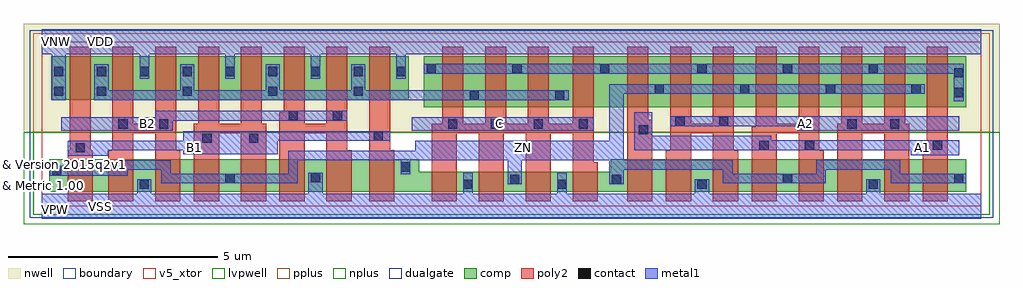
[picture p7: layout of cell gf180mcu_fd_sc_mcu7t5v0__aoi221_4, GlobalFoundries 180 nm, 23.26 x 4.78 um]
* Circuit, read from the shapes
.subckt gf180mcu_fd_sc_mcu7t5v0__aoi221_4 A1 A2 B1 B2 C VDD VNW VSS ZN
XM1 n1 B1 ZN VSUBS nfet_05v0 w=0.77u l=0.6u
XM2 VSS B2 n1 VSUBS nfet_05v0 w=0.77u l=0.6u
XM3 n2 B2 VSS VSUBS nfet_05v0 w=0.77u l=0.6u
XM4 ZN B1 n2 VSUBS nfet_05v0 w=0.77u l=0.6u
XM5 n3 B1 ZN VSUBS nfet_05v0 w=0.77u l=0.6u
XM6 VSS B2 n3 VSUBS nfet_05v0 w=0.77u l=0.6u
XM7 n4 B2 VSS VSUBS nfet_05v0 w=0.77u l=0.6u
XM8 ZN B1 n4 VSUBS nfet_05v0 w=0.77u l=0.6u
XM9 VSS C ZN VSUBS nfet_05v0 w=0.48u l=0.6u m=4
XM10 n5 A1 ZN VSUBS nfet_05v0 w=0.77u l=0.6u
XM11 VSS A2 n5 VSUBS nfet_05v0 w=0.77u l=0.6u
XM12 n6 A2 VSS VSUBS nfet_05v0 w=0.77u l=0.6u
XM13 ZN A1 n6 VSUBS nfet_05v0 w=0.77u l=0.6u
XM14 n7 A1 ZN VSUBS nfet_05v0 w=0.77u l=0.6u
XM15 VSS A2 n7 VSUBS nfet_05v0 w=0.77u l=0.6u
XM16 n8 A2 VSS VSUBS nfet_05v0 w=0.77u l=0.6u
XM17 ZN A1 n8 VSUBS nfet_05v0 w=0.77u l=0.6u
XM18 n9 B1 VDD VNW pfet_05v0 w=1.035u l=0.5u m=4
XM19 VDD B2 n9 VNW pfet_05v0 w=1.035u l=0.5u m=4
XM20 n9 C n10 VNW pfet_05v0 w=1.215u l=0.5u m=4
XM21 ZN A1 n10 VNW pfet_05v0 w=1.215u l=0.5u m=4
XM22 n10 A2 ZN VNW pfet_05v0 w=1.215u l=0.5u m=4
.ends

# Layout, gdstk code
import gdstk
lib = gdstk.Library(unit=1e-6, precision=1e-09)
def R(c, l, rs):  # rectangles x0, y0, x1, y1
    for r in rs: c.add(gdstk.rectangle(r[:2], r[2:], *l))
def A(c, l, x, y, w, h, nx, ny, dx, dy):  # array of equal rectangles
    R(c, l, [(x+i*dx, y+j*dy, x+i*dx+w, y+j*dy+h) for i in range(nx) for j in range(ny)])
def P(c, l, *ps):  # polygons
    for p in ps: c.add(gdstk.Polygon(p, *l))
boundary = (0, 0)
nwell = (21, 0)
comp = (22, 0)
poly2 = (30, 0)
pplus = (31, 0)
nplus = (32, 0)
contact = (33, 0)
metal1 = (34, 0)
dualgate = (55, 0)
v5_xtor = (112, 1)
lvpwell = (204, 0)

gf180mcu_fd_sc_mcu7t5v0_ = lib.new_cell('gf180mcu_fd_sc_mcu7t5v0__aoi221_4')
R(gf180mcu_fd_sc_mcu7t5v0_, boundary, [(0,0,22.4,3.92)])
R(gf180mcu_fd_sc_mcu7t5v0_, nwell, [(-0.43,1.76,22.83,4.35)])
R(gf180mcu_fd_sc_mcu7t5v0_, comp, [(9.11,2.36,22.04,3.575), (0.23,2.54,8.75,3.575)])
P(gf180mcu_fd_sc_mcu7t5v0_, comp, [(0.18,0.345),(0.18,1.115),(9,1.115),(9,0.825),(13.56,0.825),(13.56,1.115),(22.04,1.115),(22.04,0.345)])
P(gf180mcu_fd_sc_mcu7t5v0_, poly2, [(0.62,0.12),(0.62,1.335),(0.67,1.335),(0.67,3.8),(1.17,3.8),(1.17,1.335),(1.22,1.335),(1.22,0.12)],
  [(1.59,0.12),(1.59,1.335),(1.69,1.335),(1.69,3.8),(2.19,3.8),(2.19,1.97),(2.71,1.97),(2.71,3.8),(3.21,3.8),(3.21,1.335),(3.31,1.335),(3.31,0.12),(2.71,0.12),(2.71,1.74),(2.19,1.74),(2.19,0.12)],
  [(3.63,0.12),(3.63,1.97),(3.73,1.97),(3.73,3.8),(4.23,3.8),(4.23,1.97),(4.75,1.97),(4.75,3.8),(5.25,3.8),(5.25,1.97),(5.35,1.97),(5.35,0.12),(4.75,0.12),(4.75,1.74),(4.23,1.74),(4.23,0.12)],
  [(5.67,0.12),(5.67,2.24),(5.77,2.24),(5.77,3.8),(6.27,3.8),(6.27,1.97),(6.79,1.97),(6.79,3.8),(7.29,3.8),(7.29,1.335),(7.39,1.335),(7.39,0.12),(6.79,0.12),(6.79,1.74),(6.27,1.74),(6.27,0.12)],
  [(7.81,0.12),(7.81,3.8),(8.31,3.8),(8.31,1.335),(8.41,1.335),(8.41,0.12)],
  [(9.3,0.12),(9.3,1.97),(9.55,1.97),(9.55,3.8),(10.05,3.8),(10.05,1.97),(10.57,1.97),(10.57,3.8),(11.07,3.8),(11.07,1.97),(11.59,1.97),(11.59,3.8),(12.09,3.8),(12.09,1.97),(12.66,1.97),(12.66,3.8),(13.16,3.8),(13.16,1.045),(13.26,1.045),(13.26,0.12),(12.66,0.12),(12.66,1.74),(12.14,1.74),(12.14,0.12),(11.54,0.12),(11.54,1.74),(11.02,1.74),(11.02,0.12),(10.42,0.12),(10.42,1.74),(9.9,1.74),(9.9,0.12)],
  [(13.96,0.12),(13.96,3.8),(14.46,3.8),(14.46,2.06),(14.56,2.06),(14.56,0.12)],
  [(14.88,0.12),(14.88,1.335),(14.98,1.335),(14.98,3.8),(15.48,3.8),(15.48,1.97),(16,1.97),(16,3.8),(16.5,3.8),(16.5,1.335),(16.6,1.335),(16.6,0.12),(16,0.12),(16,1.74),(15.48,1.74),(15.48,0.12)],
  [(16.92,0.12),(16.92,1.89),(17.02,1.89),(17.02,3.8),(17.52,3.8),(17.52,1.97),(18.04,1.97),(18.04,3.8),(18.54,3.8),(18.54,1.335),(18.64,1.335),(18.64,0.12),(18.04,0.12),(18.04,1.74),(17.52,1.74),(17.52,0.12)],
  [(18.96,0.12),(18.96,1.97),(19.06,1.97),(19.06,3.8),(19.56,3.8),(19.56,1.97),(20.08,1.97),(20.08,3.8),(20.58,3.8),(20.58,1.97),(20.68,1.97),(20.68,0.12),(20.08,0.12),(20.08,1.74),(19.56,1.74),(19.56,0.12)],
  [(21,0.12),(21,1.335),(21.1,1.335),(21.1,3.8),(21.6,3.8),(21.6,0.12)])
R(gf180mcu_fd_sc_mcu7t5v0_, pplus, [(-0.2,1.76,22.6,4.12)])
R(gf180mcu_fd_sc_mcu7t5v0_, nplus, [(-0.2,-0.2,22.6,1.76)])
A(gf180mcu_fd_sc_mcu7t5v0_, contact, 9.69, 1.85, 0.22, 0.22, 3, 1, 1.02, 0)
A(gf180mcu_fd_sc_mcu7t5v0_, contact, 1.32, 2.63, 0.22, 0.22, 4, 1, 2.04, 0)
A(gf180mcu_fd_sc_mcu7t5v0_, contact, 14.61, 2.685, 0.22, 0.22, 4, 1, 2.04, 0)
A(gf180mcu_fd_sc_mcu7t5v0_, contact, 0.3, 3.1, 0.22, 0.22, 9, 1, 1.02, 0)
A(gf180mcu_fd_sc_mcu7t5v0_, contact, 15.63, 3.165, 0.22, 0.22, 3, 1, 2.04, 0)
R(gf180mcu_fd_sc_mcu7t5v0_, contact, [(2.34,0.415,2.56,0.635), (10.05,0.415,10.27,0.635), (12.29,0.415,12.51,0.635), (15.63,0.415,15.85,0.635), (19.71,0.415,19.93,0.635), (11.17,0.535,11.39,0.755), (13.59,0.535,13.81,0.755), (4.38,0.55,4.6,0.77), (17.67,0.55,17.89,0.77), (21.75,0.55,21.97,0.77), (6.42,0.57,6.64,0.79), (0.25,0.735,0.47,0.955), (8.56,0.825,8.78,1.045), (0.81,1.285,1.03,1.505), (17.11,1.345,17.33,1.565), (18.19,1.345,18.41,1.565), (21.245,1.345,21.465,1.565), (3.835,1.51,4.055,1.73), (4.945,1.51,5.165,1.73), (7.915,1.565,8.135,1.785), (14.235,1.715,14.455,1.935), (1.83,1.85,2.05,2.07), (2.805,1.85,3.025,2.07), (12.8,1.85,13.02,2.07), (19.205,1.85,19.425,2.07), (20.225,1.85,20.445,2.07), (15.105,1.915,15.325,2.135), (16.15,1.915,16.37,2.135), (5.89,2.045,6.11,2.265), (6.945,2.045,7.165,2.265), (10.2,2.535,10.42,2.755), (12.24,2.535,12.46,2.755), (21.75,2.6,21.97,2.82), (0.3,2.63,0.52,2.85), (21.75,3.07,21.97,3.29), (9.18,3.165,9.4,3.385), (11.22,3.165,11.44,3.385), (13.31,3.165,13.53,3.385)])
R(gf180mcu_fd_sc_mcu7t5v0_, metal1, [(8.82,1.8,13.16,2.12)])
P(gf180mcu_fd_sc_mcu7t5v0_, metal1, [(0.465,1.8),(0.465,2.12),(2.71,2.12),(2.71,2.27),(7.29,2.27),(7.29,2.04),(3.125,2.04),(3.125,1.8)],
  [(0.62,1.2),(0.62,1.56),(3.38,1.56),(3.38,1.79),(8.31,1.79),(8.31,1.555),(5.63,1.555),(5.63,1.24),(3.38,1.24),(3.38,1.33),(1.59,1.33),(1.59,1.2)],
  [(1.26,2.53),(1.26,3.38),(1.6,3.38),(1.6,2.76),(3.3,2.76),(3.3,3.38),(3.64,3.38),(3.64,2.76),(5.34,2.76),(5.34,3.38),(5.68,3.38),(5.68,2.76),(7.38,2.76),(7.38,3.38),(7.72,3.38),(7.72,2.76),(12.56,2.76),(12.56,2.53)],
  [(20.72,1.22),(20.72,1.335),(14.12,1.335),(14.12,2.245),(14.55,2.245),(14.55,1.675),(17.39,1.675),(17.39,1.57),(21.865,1.57),(21.865,1.22)],
  [(18.01,1.8),(18.01,1.91),(14.98,1.91),(14.98,2.14),(21.865,2.14),(21.865,1.8)],
  [(21.745,2.5),(21.745,3.16),(9.11,3.16),(9.11,3.39),(21.975,3.39),(21.975,2.5)],
  [(11.11,0.53),(11.11,1.095),(8.785,1.095),(8.785,0.765),(8.555,0.765),(8.555,1.095),(6.11,1.095),(6.11,0.545),(2.85,0.545),(2.85,0.87),(2.05,0.87),(2.05,0.73),(0.19,0.73),(0.19,0.96),(1.82,0.96),(1.82,1.1),(3.08,1.1),(3.08,0.78),(5.88,0.78),(5.88,1.325),(8.905,1.325),(8.905,1.56),(13.53,1.56),(13.53,2.91),(21.05,2.91),(21.05,2.68),(13.88,2.68),(13.88,1.105),(16.47,1.105),(16.47,0.78),(18.46,0.78),(18.46,1.105),(20.47,1.105),(20.47,0.775),(22.04,0.775),(22.04,0.545),(20.24,0.545),(20.24,0.87),(18.69,0.87),(18.69,0.545),(16.24,0.545),(16.24,0.875),(13.87,0.875),(13.87,0.53),(13.53,0.53),(13.53,1.095),(11.45,1.095),(11.45,0.53)],
  [(0,-0.3),(0,0.3),(2.28,0.3),(2.28,0.64),(2.62,0.64),(2.62,0.3),(6.36,0.3),(6.36,0.795),(6.7,0.795),(6.7,0.3),(10.045,0.3),(10.045,0.795),(10.275,0.795),(10.275,0.3),(12.285,0.3),(12.285,0.795),(12.515,0.795),(12.515,0.3),(15.57,0.3),(15.57,0.64),(15.91,0.64),(15.91,0.3),(19.65,0.3),(19.65,0.64),(19.99,0.64),(19.99,0.3),(22.4,0.3),(22.4,-0.3)],
  [(0.24,2.53),(0.24,3.62),(0,3.62),(0,4.22),(22.4,4.22),(22.4,3.62),(8.685,3.62),(8.685,3.04),(8.455,3.04),(8.455,3.62),(6.645,3.62),(6.645,3.04),(6.415,3.04),(6.415,3.62),(4.605,3.62),(4.605,3.04),(4.375,3.04),(4.375,3.62),(2.565,3.62),(2.565,3.04),(2.335,3.04),(2.335,3.62),(0.58,3.62),(0.58,2.53)])
R(gf180mcu_fd_sc_mcu7t5v0_, dualgate, [(-0.28,-0.28,22.68,4.2)])
R(gf180mcu_fd_sc_mcu7t5v0_, v5_xtor, [(0,0,22.4,3.92)])
R(gf180mcu_fd_sc_mcu7t5v0_, lvpwell, [(-0.43,-0.43,22.83,1.76)])
gf180mcu_fd_sc_mcu7t5v0_.add(gdstk.Label('A2', (18.2,1.96), layer=34, texttype=10))
gf180mcu_fd_sc_mcu7t5v0_.add(gdstk.Label('B1', (3.64,1.4), layer=34, texttype=10))
gf180mcu_fd_sc_mcu7t5v0_.add(gdstk.Label('B2', (2.52,1.96), layer=34, texttype=10))
gf180mcu_fd_sc_mcu7t5v0_.add(gdstk.Label('C', (10.92,1.96), layer=34, texttype=10))
gf180mcu_fd_sc_mcu7t5v0_.add(gdstk.Label('VDD', (1.4,3.92), layer=34, texttype=10))
gf180mcu_fd_sc_mcu7t5v0_.add(gdstk.Label('VSS', (1.4,0), layer=34, texttype=10))
gf180mcu_fd_sc_mcu7t5v0_.add(gdstk.Label('ZN', (11.48,1.4), layer=34, texttype=10))
gf180mcu_fd_sc_mcu7t5v0_.add(gdstk.Label('A1', (21,1.4), layer=34, texttype=10))
gf180mcu_fd_sc_mcu7t5v0_.add(gdstk.Label('& Vendor GLOBALFOUNDRIES', (0,2), layer=63, texttype=63))
gf180mcu_fd_sc_mcu7t5v0_.add(gdstk.Label('& Product GF018hv5v_mcu_sc7', (0,1.5), layer=63, texttype=63))
gf180mcu_fd_sc_mcu7t5v0_.add(gdstk.Label('& Version 2015q2v1', (0,1), layer=63, texttype=63))
gf180mcu_fd_sc_mcu7t5v0_.add(gdstk.Label('& Metric 1.00', (0,0.5), layer=63, texttype=63))
gf180mcu_fd_sc_mcu7t5v0_.add(gdstk.Label('VNW', (0.345,3.92), layer=21, texttype=10))
gf180mcu_fd_sc_mcu7t5v0_.add(gdstk.Label('VPW', (0.34,-0.085), layer=204, texttype=10))

lib.write_gds('gf180mcu_fd_sc_mcu7t5v0__aoi221_4.gds')
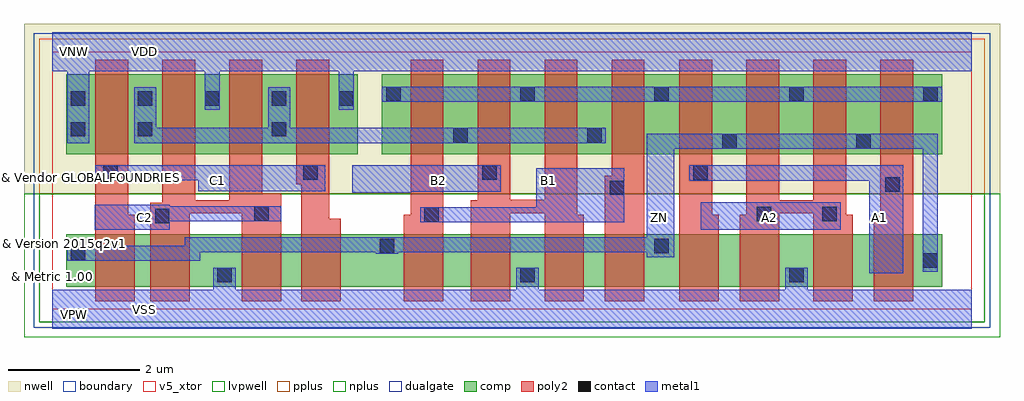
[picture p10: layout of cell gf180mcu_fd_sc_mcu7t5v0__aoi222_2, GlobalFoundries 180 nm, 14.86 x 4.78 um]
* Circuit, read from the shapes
.subckt gf180mcu_fd_sc_mcu7t5v0__aoi222_2 A1 A2 B1 B2 C1 C2 VDD VNW VSS ZN
XM1 n1 C1 ZN VSUBS nfet_05v0 w=0.8u l=0.6u
XM2 VSS C2 n1 VSUBS nfet_05v0 w=0.8u l=0.6u
XM3 n2 C2 VSS VSUBS nfet_05v0 w=0.8u l=0.6u
XM4 ZN C1 n2 VSUBS nfet_05v0 w=0.8u l=0.6u
XM5 n3 B1 ZN VSUBS nfet_05v0 w=0.8u l=0.6u
XM6 VSS B2 n3 VSUBS nfet_05v0 w=0.8u l=0.6u
XM7 n4 B2 VSS VSUBS nfet_05v0 w=0.8u l=0.6u
XM8 ZN B1 n4 VSUBS nfet_05v0 w=0.8u l=0.6u
XM9 n5 A1 ZN VSUBS nfet_05v0 w=0.8u l=0.6u
XM10 VSS A2 n5 VSUBS nfet_05v0 w=0.8u l=0.6u
XM11 n6 A2 VSS VSUBS nfet_05v0 w=0.8u l=0.6u
XM12 ZN A1 n6 VSUBS nfet_05v0 w=0.8u l=0.6u
XM13 n7 C1 VDD VNW pfet_05v0 w=1.22u l=0.5u m=2
XM14 VDD C2 n7 VNW pfet_05v0 w=1.22u l=0.5u m=2
XM15 n7 B1 n8 VNW pfet_05v0 w=1.22u l=0.5u m=2
XM16 n8 B2 n7 VNW pfet_05v0 w=1.22u l=0.5u m=2
XM17 ZN A1 n8 VNW pfet_05v0 w=1.22u l=0.5u m=2
XM18 n8 A2 ZN VNW pfet_05v0 w=1.22u l=0.5u m=2
.ends

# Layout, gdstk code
import gdstk
lib = gdstk.Library(unit=1e-6, precision=1e-09)
def R(c, l, rs):  # rectangles x0, y0, x1, y1
    for r in rs: c.add(gdstk.rectangle(r[:2], r[2:], *l))
def A(c, l, x, y, w, h, nx, ny, dx, dy):  # array of equal rectangles
    R(c, l, [(x+i*dx, y+j*dy, x+i*dx+w, y+j*dy+h) for i in range(nx) for j in range(ny)])
def P(c, l, *ps):  # polygons
    for p in ps: c.add(gdstk.Polygon(p, *l))
boundary = (0, 0)
nwell = (21, 0)
comp = (22, 0)
poly2 = (30, 0)
pplus = (31, 0)
nplus = (32, 0)
contact = (33, 0)
metal1 = (34, 0)
dualgate = (55, 0)
v5_xtor = (112, 1)
lvpwell = (204, 0)

gf180mcu_fd_sc_mcu7t5v0_ = lib.new_cell('gf180mcu_fd_sc_mcu7t5v0__aoi222_2')
R(gf180mcu_fd_sc_mcu7t5v0_, boundary, [(0,0,14,3.92)])
R(gf180mcu_fd_sc_mcu7t5v0_, nwell, [(-0.43,1.76,14.43,4.35)])
R(gf180mcu_fd_sc_mcu7t5v0_, comp, [(0.215,0.34,13.55,1.14), (0.215,2.36,4.655,3.58), (5.015,2.36,13.55,3.58)])
P(gf180mcu_fd_sc_mcu7t5v0_, poly2, [(0.655,0.12),(0.655,3.8),(1.155,3.8),(1.155,1.44),(1.255,1.44),(1.255,0.12)],
  [(1.495,0.12),(1.495,1.62),(1.675,1.62),(1.675,3.8),(2.175,3.8),(2.175,1.66),(2.695,1.66),(2.695,3.8),(3.195,3.8),(3.195,1.755),(3.485,1.755),(3.485,0.12),(2.885,0.12),(2.885,1.46),(2.095,1.46),(2.095,0.12)],
  [(3.795,0.12),(3.795,1.9),(3.715,1.9),(3.715,3.8),(4.215,3.8),(4.215,1.38),(4.395,1.38),(4.395,0.12)],
  [(5.355,0.12),(5.355,1.44),(5.455,1.44),(5.455,3.8),(5.955,3.8),(5.955,0.12)],
  [(6.375,0.12),(6.375,1.66),(6.475,1.66),(6.475,3.8),(6.975,3.8),(6.975,1.665),(7.495,1.665),(7.495,3.8),(7.995,3.8),(7.995,1.44),(8.095,1.44),(8.095,0.12),(7.495,0.12),(7.495,1.465),(6.975,1.465),(6.975,0.12)],
  [(8.415,0.12),(8.415,2.03),(8.515,2.03),(8.515,3.8),(9.015,3.8),(9.015,0.12)],
  [(9.55,0.12),(9.55,3.8),(10.05,3.8),(10.05,1.44),(10.15,1.44),(10.15,0.12)],
  [(10.47,0.12),(10.47,1.44),(10.57,1.44),(10.57,3.8),(11.07,3.8),(11.07,1.66),(11.59,1.66),(11.59,3.8),(12.09,3.8),(12.09,1.44),(12.19,1.44),(12.19,0.12),(11.59,0.12),(11.59,1.46),(11.07,1.46),(11.07,0.12)],
  [(12.51,0.12),(12.51,1.44),(12.61,1.44),(12.61,3.8),(13.11,3.8),(13.11,0.12)])
R(gf180mcu_fd_sc_mcu7t5v0_, pplus, [(-0.2,1.76,14.2,4.12)])
R(gf180mcu_fd_sc_mcu7t5v0_, nplus, [(-0.2,-0.2,14.2,1.76)])
A(gf180mcu_fd_sc_mcu7t5v0_, contact, 0.285, 3.1, 0.22, 0.22, 5, 1, 1.02, 0)
A(gf180mcu_fd_sc_mcu7t5v0_, contact, 5.085, 3.165, 0.22, 0.22, 3, 1, 2.04, 0)
R(gf180mcu_fd_sc_mcu7t5v0_, contact, [(2.515,0.41,2.735,0.63), (7.125,0.41,7.345,0.63), (11.22,0.41,11.44,0.63), (13.26,0.63,13.48,0.85), (0.285,0.745,0.505,0.965), (4.985,0.85,5.205,1.07), (9.165,0.85,9.385,1.07), (1.565,1.31,1.785,1.53), (5.665,1.33,5.885,1.55), (10.725,1.34,10.945,1.56), (11.725,1.34,11.945,1.56), (3.075,1.345,3.295,1.565), (8.485,1.74,8.705,1.96), (12.68,1.79,12.9,2.01), (0.78,1.97,1,2.19), (3.825,1.97,4.045,2.19), (6.545,1.97,6.765,2.19), (9.76,1.97,9.98,2.19), (10.2,2.445,10.42,2.665), (12.24,2.445,12.46,2.665), (6.105,2.535,6.325,2.755), (8.145,2.535,8.365,2.755), (0.285,2.63,0.505,2.85), (1.305,2.63,1.525,2.85), (3.345,2.63,3.565,2.85), (11.22,3.165,11.44,3.385), (13.26,3.165,13.48,3.385)])
R(gf180mcu_fd_sc_mcu7t5v0_, metal1, [(9.87,1.21,12.005,1.63), (5.02,3.16,13.55,3.39)])
P(gf180mcu_fd_sc_mcu7t5v0_, metal1, [(0.65,1.21),(0.65,1.59),(1.79,1.59),(1.79,1.57),(3.485,1.57),(3.485,1.34),(1.79,1.34),(1.79,1.21)],
  [(2.225,1.8),(2.225,1.965),(0.655,1.965),(0.655,2.195),(4.155,2.195),(4.155,1.8)],
  [(4.57,1.77),(4.57,2.195),(6.825,2.195),(6.825,1.785),(5.46,1.785),(5.46,1.77)],
  [(1.245,2.53),(1.245,3.38),(1.585,3.38),(1.585,2.76),(3.285,2.76),(3.285,3.38),(3.625,3.38),(3.625,2.76),(8.425,2.76),(8.425,2.53)],
  [(5.605,1.325),(5.605,1.555),(7.37,1.555),(7.37,2.15),(8.71,2.15),(8.71,1.325)],
  [(12.44,0.55),(12.44,1.96),(9.7,1.96),(9.7,2.195),(12.96,2.195),(12.96,0.55)],
  [(13.255,0.57),(13.255,2.44),(9.47,2.44),(9.47,0.79),(9.05,0.79),(9.05,0.865),(5.265,0.865),(5.265,0.845),(4.925,0.845),(4.925,0.865),(2.25,0.865),(2.25,0.74),(0.225,0.74),(0.225,0.97),(2.02,0.97),(2.02,1.095),(9.05,1.095),(9.05,2.67),(13.485,2.67),(13.485,0.57)],
  [(0,-0.3),(0,0.3),(2.455,0.3),(2.455,0.635),(2.795,0.635),(2.795,0.3),(7.065,0.3),(7.065,0.635),(7.405,0.635),(7.405,0.3),(11.16,0.3),(11.16,0.635),(11.5,0.635),(11.5,0.3),(14,0.3),(14,-0.3)],
  [(0.225,2.53),(0.225,3.62),(0,3.62),(0,4.22),(14,4.22),(14,3.62),(4.59,3.62),(4.59,3.04),(4.36,3.04),(4.36,3.62),(2.55,3.62),(2.55,3.04),(2.32,3.04),(2.32,3.62),(0.565,3.62),(0.565,2.53)])
R(gf180mcu_fd_sc_mcu7t5v0_, dualgate, [(-0.28,-0.28,14.28,4.2)])
R(gf180mcu_fd_sc_mcu7t5v0_, v5_xtor, [(0,0,14,3.92)])
R(gf180mcu_fd_sc_mcu7t5v0_, lvpwell, [(-0.43,-0.43,14.43,1.76)])
gf180mcu_fd_sc_mcu7t5v0_.add(gdstk.Label('B2', (5.88,1.96), layer=34, texttype=10))
gf180mcu_fd_sc_mcu7t5v0_.add(gdstk.Label('B1', (7.56,1.96), layer=34, texttype=10))
gf180mcu_fd_sc_mcu7t5v0_.add(gdstk.Label('A2', (10.92,1.4), layer=34, texttype=10))
gf180mcu_fd_sc_mcu7t5v0_.add(gdstk.Label('A1', (12.6,1.4), layer=34, texttype=10))
gf180mcu_fd_sc_mcu7t5v0_.add(gdstk.Label('ZN', (9.24,1.4), layer=34, texttype=10))
gf180mcu_fd_sc_mcu7t5v0_.add(gdstk.Label('VSS', (1.4,0), layer=34, texttype=10))
gf180mcu_fd_sc_mcu7t5v0_.add(gdstk.Label('VDD', (1.4,3.92), layer=34, texttype=10))
gf180mcu_fd_sc_mcu7t5v0_.add(gdstk.Label('C2', (1.4,1.4), layer=34, texttype=10))
gf180mcu_fd_sc_mcu7t5v0_.add(gdstk.Label('C1', (2.52,1.96), layer=34, texttype=10))
gf180mcu_fd_sc_mcu7t5v0_.add(gdstk.Label('& Vendor GLOBALFOUNDRIES', (0,2), layer=63, texttype=63))
gf180mcu_fd_sc_mcu7t5v0_.add(gdstk.Label('& Product GF018hv5v_mcu_sc7', (0,1.5), layer=63, texttype=63))
gf180mcu_fd_sc_mcu7t5v0_.add(gdstk.Label('& Version 2015q2v1', (0,1), layer=63, texttype=63))
gf180mcu_fd_sc_mcu7t5v0_.add(gdstk.Label('& Metric 1.00', (0,0.5), layer=63, texttype=63))
gf180mcu_fd_sc_mcu7t5v0_.add(gdstk.Label('VNW', (0.345,3.92), layer=21, texttype=10))
gf180mcu_fd_sc_mcu7t5v0_.add(gdstk.Label('VPW', (0.34,-0.085), layer=204, texttype=10))

lib.write_gds('gf180mcu_fd_sc_mcu7t5v0__aoi222_2.gds')
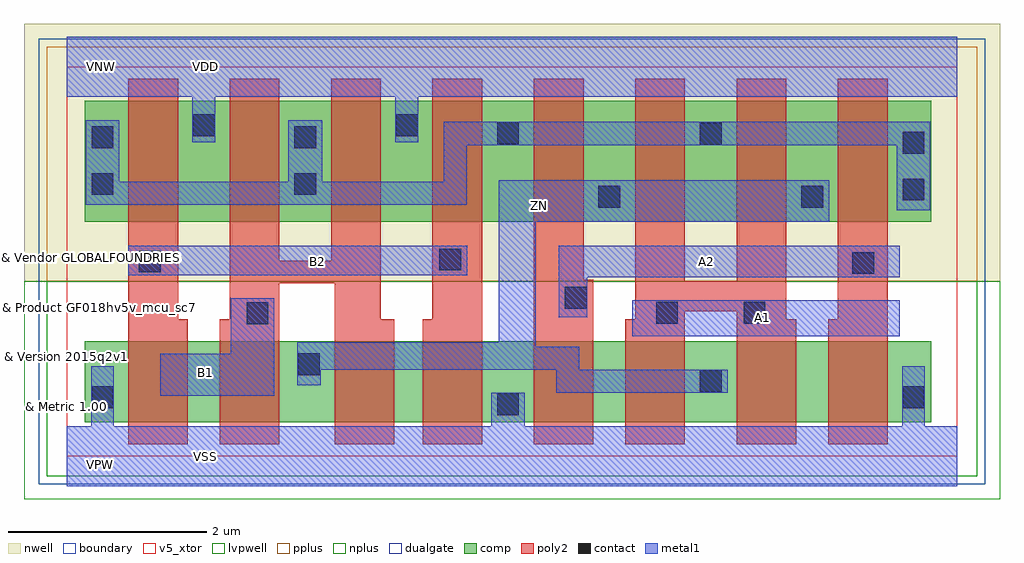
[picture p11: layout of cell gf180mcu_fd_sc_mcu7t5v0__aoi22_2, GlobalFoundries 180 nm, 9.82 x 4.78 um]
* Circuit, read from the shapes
.subckt gf180mcu_fd_sc_mcu7t5v0__aoi22_2 A1 A2 B1 B2 VDD VNW VSS ZN
XM1 n1 B2 VSS VSUBS nfet_05v0 w=0.815u l=0.6u
XM2 ZN B1 n1 VSUBS nfet_05v0 w=0.815u l=0.6u
XM3 n2 B1 ZN VSUBS nfet_05v0 w=0.815u l=0.6u
XM4 VSS B2 n2 VSUBS nfet_05v0 w=0.815u l=0.6u
XM5 n3 A2 VSS VSUBS nfet_05v0 w=0.815u l=0.6u
XM6 ZN A1 n3 VSUBS nfet_05v0 w=0.815u l=0.6u
XM7 n4 A1 ZN VSUBS nfet_05v0 w=0.815u l=0.6u
XM8 VSS A2 n4 VSUBS nfet_05v0 w=0.815u l=0.6u
XM9 VDD B2 n5 VNW pfet_05v0 w=1.215u l=0.5u m=2
XM10 n5 B1 VDD VNW pfet_05v0 w=1.215u l=0.5u m=2
XM11 ZN A2 n5 VNW pfet_05v0 w=1.215u l=0.5u m=2
XM12 n5 A1 ZN VNW pfet_05v0 w=1.215u l=0.5u m=2
.ends

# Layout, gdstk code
import gdstk
lib = gdstk.Library(unit=1e-6, precision=1e-09)
def R(c, l, rs):  # rectangles x0, y0, x1, y1
    for r in rs: c.add(gdstk.rectangle(r[:2], r[2:], *l))
def P(c, l, *ps):  # polygons
    for p in ps: c.add(gdstk.Polygon(p, *l))
boundary = (0, 0)
nwell = (21, 0)
comp = (22, 0)
poly2 = (30, 0)
pplus = (31, 0)
nplus = (32, 0)
contact = (33, 0)
metal1 = (34, 0)
dualgate = (55, 0)
v5_xtor = (112, 1)
lvpwell = (204, 0)

gf180mcu_fd_sc_mcu7t5v0_ = lib.new_cell('gf180mcu_fd_sc_mcu7t5v0__aoi22_2')
R(gf180mcu_fd_sc_mcu7t5v0_, boundary, [(0,0,8.96,3.92)])
R(gf180mcu_fd_sc_mcu7t5v0_, nwell, [(-0.43,1.76,9.39,4.35)])
R(gf180mcu_fd_sc_mcu7t5v0_, comp, [(0.18,0.345,8.7,1.16), (0.18,2.36,8.7,3.575)])
P(gf180mcu_fd_sc_mcu7t5v0_, poly2, [(0.62,0.12),(0.62,3.8),(1.12,3.8),(1.12,1.38),(1.22,1.38),(1.22,0.12)],
  [(1.54,0.12),(1.54,1.38),(1.64,1.38),(1.64,3.8),(2.14,3.8),(2.14,1.97),(2.66,1.97),(2.66,3.8),(3.16,3.8),(3.16,1.38),(3.295,1.38),(3.295,0.12),(2.695,0.12),(2.695,1.74),(2.14,1.74),(2.14,0.12)],
  [(3.58,0.12),(3.58,1.38),(3.68,1.38),(3.68,3.8),(4.18,3.8),(4.18,0.12)],
  [(4.7,0.12),(4.7,3.8),(5.2,3.8),(5.2,1.775),(5.3,1.775),(5.3,0.12)],
  [(5.62,0.12),(5.62,1.38),(5.72,1.38),(5.72,3.8),(6.22,3.8),(6.22,1.76),(6.74,1.76),(6.74,3.8),(7.24,3.8),(7.24,1.38),(7.34,1.38),(7.34,0.12),(6.74,0.12),(6.74,1.46),(6.22,1.46),(6.22,0.12)],
  [(7.66,0.12),(7.66,1.38),(7.76,1.38),(7.76,3.8),(8.26,3.8),(8.26,0.12)])
R(gf180mcu_fd_sc_mcu7t5v0_, pplus, [(-0.2,1.76,9.16,4.12)])
R(gf180mcu_fd_sc_mcu7t5v0_, nplus, [(-0.2,-0.2,9.16,1.76)])
R(gf180mcu_fd_sc_mcu7t5v0_, contact, [(4.33,0.415,4.55,0.635), (0.25,0.485,0.47,0.705), (8.41,0.485,8.63,0.705), (6.37,0.645,6.59,0.865), (2.325,0.815,2.545,1.035), (1.81,1.33,2.03,1.55), (5.93,1.335,6.15,1.555), (6.81,1.335,7.03,1.555), (5.01,1.485,5.23,1.705), (7.905,1.835,8.125,2.055), (0.725,1.85,0.945,2.07), (3.75,1.87,3.97,2.09), (5.35,2.5,5.57,2.72), (7.39,2.5,7.61,2.72), (8.41,2.575,8.63,2.795), (0.25,2.63,0.47,2.85), (2.29,2.63,2.51,2.85), (8.41,3.045,8.63,3.265), (0.25,3.1,0.47,3.32), (2.29,3.1,2.51,3.32), (6.37,3.135,6.59,3.355), (4.33,3.14,4.55,3.36), (1.27,3.22,1.49,3.44), (3.31,3.22,3.53,3.44)])
R(gf180mcu_fd_sc_mcu7t5v0_, metal1, [(5.69,1.21,8.38,1.57), (0.62,1.82,4.03,2.12)])
P(gf180mcu_fd_sc_mcu7t5v0_, metal1, [(0.94,0.61),(0.94,1.03),(1.65,1.03),(1.65,1.59),(2.09,1.59),(2.09,0.61)],
  [(4.925,0.64),(4.925,0.87),(2.555,0.87),(2.555,0.715),(2.32,0.715),(2.32,1.15),(4.345,1.15),(4.345,2.78),(7.67,2.78),(7.67,2.36),(4.72,2.36),(4.72,1.1),(5.155,1.1),(5.155,0.87),(6.65,0.87),(6.65,0.64)],
  [(4.95,1.4),(4.95,2.12),(8.38,2.12),(8.38,1.8),(5.235,1.8),(5.235,1.4)],
  [(8.35,2.475),(8.35,3.13),(4.025,3.13),(4.025,2.53),(0.19,2.53),(0.19,3.38),(0.53,3.38),(0.53,2.76),(2.23,2.76),(2.23,3.38),(2.57,3.38),(2.57,2.76),(3.795,2.76),(3.795,3.365),(8.69,3.365),(8.69,2.475)],
  [(0,-0.3),(0,0.3),(0.245,0.3),(0.245,0.905),(0.475,0.905),(0.475,0.3),(4.27,0.3),(4.27,0.64),(4.61,0.64),(4.61,0.3),(8.405,0.3),(8.405,0.905),(8.635,0.905),(8.635,0.3),(8.96,0.3),(8.96,-0.3)],
  [(1.265,3.16),(1.265,3.62),(0,3.62),(0,4.22),(8.96,4.22),(8.96,3.62),(3.535,3.62),(3.535,3.16),(3.305,3.16),(3.305,3.62),(1.495,3.62),(1.495,3.16)])
R(gf180mcu_fd_sc_mcu7t5v0_, dualgate, [(-0.28,-0.28,9.24,4.2)])
R(gf180mcu_fd_sc_mcu7t5v0_, v5_xtor, [(0,0,8.96,3.92)])
R(gf180mcu_fd_sc_mcu7t5v0_, lvpwell, [(-0.43,-0.43,9.39,1.76)])
gf180mcu_fd_sc_mcu7t5v0_.add(gdstk.Label('B1', (1.4,0.84), layer=34, texttype=10))
gf180mcu_fd_sc_mcu7t5v0_.add(gdstk.Label('B2', (2.52,1.96), layer=34, texttype=10))
gf180mcu_fd_sc_mcu7t5v0_.add(gdstk.Label('VDD', (1.4,3.92), layer=34, texttype=10))
gf180mcu_fd_sc_mcu7t5v0_.add(gdstk.Label('VSS', (1.4,0), layer=34, texttype=10))
gf180mcu_fd_sc_mcu7t5v0_.add(gdstk.Label('ZN', (4.76,2.52), layer=34, texttype=10))
gf180mcu_fd_sc_mcu7t5v0_.add(gdstk.Label('A1', (7,1.4), layer=34, texttype=10))
gf180mcu_fd_sc_mcu7t5v0_.add(gdstk.Label('A2', (6.44,1.96), layer=34, texttype=10))
gf180mcu_fd_sc_mcu7t5v0_.add(gdstk.Label('& Vendor GLOBALFOUNDRIES', (0,2), layer=63, texttype=63))
gf180mcu_fd_sc_mcu7t5v0_.add(gdstk.Label('& Product GF018hv5v_mcu_sc7', (0,1.5), layer=63, texttype=63))
gf180mcu_fd_sc_mcu7t5v0_.add(gdstk.Label('& Version 2015q2v1', (0,1), layer=63, texttype=63))
gf180mcu_fd_sc_mcu7t5v0_.add(gdstk.Label('& Metric 1.00', (0,0.5), layer=63, texttype=63))
gf180mcu_fd_sc_mcu7t5v0_.add(gdstk.Label('VNW', (0.345,3.92), layer=21, texttype=10))
gf180mcu_fd_sc_mcu7t5v0_.add(gdstk.Label('VPW', (0.34,-0.085), layer=204, texttype=10))

lib.write_gds('gf180mcu_fd_sc_mcu7t5v0__aoi22_2.gds')
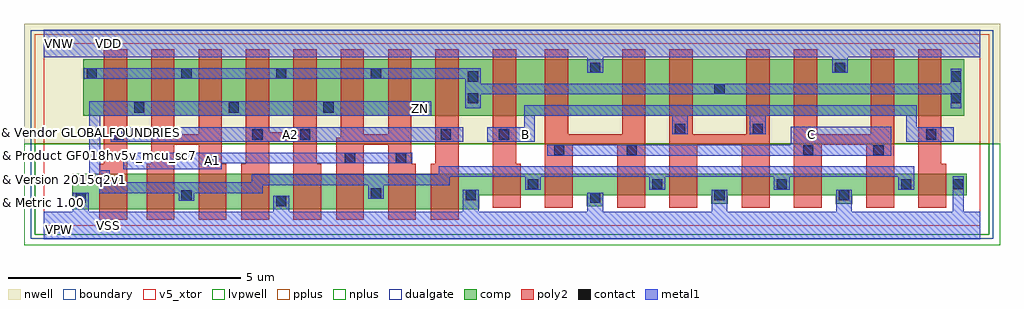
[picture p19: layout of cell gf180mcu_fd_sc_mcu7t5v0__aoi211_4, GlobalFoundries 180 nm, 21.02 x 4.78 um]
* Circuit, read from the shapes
.subckt gf180mcu_fd_sc_mcu7t5v0__aoi211_4 A1 A2 B C VDD VNW VSS ZN
XM1 n1 A2 VSS VSUBS nfet_05v0 w=0.77u l=0.6u
XM2 ZN A1 n1 VSUBS nfet_05v0 w=0.77u l=0.6u
XM3 n2 A1 ZN VSUBS nfet_05v0 w=0.77u l=0.6u
XM4 VSS A2 n2 VSUBS nfet_05v0 w=0.77u l=0.6u
XM5 n3 A2 VSS VSUBS nfet_05v0 w=0.77u l=0.6u
XM6 ZN A1 n3 VSUBS nfet_05v0 w=0.77u l=0.6u
XM7 n4 A1 ZN VSUBS nfet_05v0 w=0.77u l=0.6u
XM8 VSS A2 n4 VSUBS nfet_05v0 w=0.77u l=0.6u
XM9 ZN B VSS VSUBS nfet_05v0 w=0.46u l=0.6u m=4
XM10 VSS C ZN VSUBS nfet_05v0 w=0.46u l=0.6u m=4
XM11 ZN A2 n5 VNW pfet_05v0 w=1.22u l=0.5u m=4
XM12 n5 A1 ZN VNW pfet_05v0 w=1.22u l=0.5u m=4
XM13 n6 B n5 VNW pfet_05v0 w=1.22u l=0.5u
XM14 VDD C n6 VNW pfet_05v0 w=1.22u l=0.5u
XM15 n7 C VDD VNW pfet_05v0 w=1.22u l=0.5u
XM16 n5 B n7 VNW pfet_05v0 w=1.22u l=0.5u
XM17 n8 B n5 VNW pfet_05v0 w=1.22u l=0.5u
XM18 VDD C n8 VNW pfet_05v0 w=1.22u l=0.5u
XM19 n9 C VDD VNW pfet_05v0 w=1.22u l=0.5u
XM20 n5 B n9 VNW pfet_05v0 w=1.22u l=0.5u
.ends

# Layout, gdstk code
import gdstk
lib = gdstk.Library(unit=1e-6, precision=1e-09)
def R(c, l, rs):  # rectangles x0, y0, x1, y1
    for r in rs: c.add(gdstk.rectangle(r[:2], r[2:], *l))
def A(c, l, x, y, w, h, nx, ny, dx, dy):  # array of equal rectangles
    R(c, l, [(x+i*dx, y+j*dy, x+i*dx+w, y+j*dy+h) for i in range(nx) for j in range(ny)])
def P(c, l, *ps):  # polygons
    for p in ps: c.add(gdstk.Polygon(p, *l))
boundary = (0, 0)
nwell = (21, 0)
comp = (22, 0)
poly2 = (30, 0)
pplus = (31, 0)
nplus = (32, 0)
contact = (33, 0)
metal1 = (34, 0)
dualgate = (55, 0)
v5_xtor = (112, 1)
lvpwell = (204, 0)

gf180mcu_fd_sc_mcu7t5v0_ = lib.new_cell('gf180mcu_fd_sc_mcu7t5v0__aoi211_4')
R(gf180mcu_fd_sc_mcu7t5v0_, boundary, [(0,0,20.16,3.92)])
R(gf180mcu_fd_sc_mcu7t5v0_, nwell, [(-0.43,1.76,20.59,4.35)])
R(gf180mcu_fd_sc_mcu7t5v0_, comp, [(0.85,2.36,19.82,3.58)])
P(gf180mcu_fd_sc_mcu7t5v0_, comp, [(0.61,0.345),(0.61,1.115),(19.87,1.115),(19.87,0.655),(17.41,0.655),(17.41,0.47),(17.05,0.47),(17.05,0.655),(14.73,0.655),(14.73,0.47),(14.37,0.47),(14.37,0.655),(12.05,0.655),(12.05,0.415),(11.69,0.415),(11.69,0.655),(9.37,0.655),(9.37,0.345)])
P(gf180mcu_fd_sc_mcu7t5v0_, poly2, [(1.19,0.12),(1.19,1.335),(1.29,1.335),(1.29,3.8),(1.79,3.8),(1.79,0.12)],
  [(2.21,0.12),(2.21,1.335),(2.31,1.335),(2.31,3.8),(2.81,3.8),(2.81,1.97),(3.33,1.97),(3.33,3.8),(3.83,3.8),(3.83,1.335),(3.93,1.335),(3.93,0.12),(3.33,0.12),(3.33,1.74),(2.81,1.74),(2.81,0.12)],
  [(4.25,0.12),(4.25,1.335),(4.35,1.335),(4.35,3.8),(4.85,3.8),(4.85,2.005),(5.37,2.005),(5.37,3.8),(5.87,3.8),(5.87,1.335),(5.97,1.335),(5.97,0.12),(5.37,0.12),(5.37,1.805),(4.85,1.805),(4.85,0.12)],
  [(6.29,0.12),(6.29,1.89),(6.39,1.89),(6.39,3.8),(6.89,3.8),(6.89,1.97),(7.41,1.97),(7.41,3.8),(7.91,3.8),(7.91,1.335),(8.01,1.335),(8.01,0.12),(7.41,0.12),(7.41,1.74),(6.89,1.74),(6.89,0.12)],
  [(8.33,0.12),(8.33,1.335),(8.43,1.335),(8.43,3.8),(8.93,3.8),(8.93,0.12)],
  [(9.67,0.385),(9.67,3.8),(10.17,3.8),(10.17,1.335),(10.27,1.335),(10.27,0.385)],
  [(10.79,0.385),(10.79,3.8),(11.29,3.8),(11.29,1.97),(12.45,1.97),(12.45,3.8),(12.95,3.8),(12.95,0.385),(12.35,0.385),(12.35,1.74),(11.39,1.74),(11.39,0.385)],
  [(13.47,0.385),(13.47,3.8),(13.97,3.8),(13.97,1.97),(15.13,1.97),(15.13,3.8),(15.63,3.8),(15.63,0.385),(15.03,0.385),(15.03,1.74),(14.07,1.74),(14.07,0.385)],
  [(16.15,0.385),(16.15,3.8),(16.65,3.8),(16.65,1.97),(17.81,1.97),(17.81,3.8),(18.31,3.8),(18.31,0.385),(17.71,0.385),(17.71,1.74),(16.75,1.74),(16.75,0.385)],
  [(18.83,0.385),(18.83,3.8),(19.33,3.8),(19.33,1.335),(19.43,1.335),(19.43,0.385)])
R(gf180mcu_fd_sc_mcu7t5v0_, pplus, [(-0.2,1.76,20.36,4.12)])
R(gf180mcu_fd_sc_mcu7t5v0_, nplus, [(-0.2,-0.2,20.36,1.76)])
A(gf180mcu_fd_sc_mcu7t5v0_, contact, 10.42, 0.78, 0.22, 0.22, 4, 1, 2.68, 0)
A(gf180mcu_fd_sc_mcu7t5v0_, contact, 1.94, 2.43, 0.22, 0.22, 4, 1, 2.04, 0)
A(gf180mcu_fd_sc_mcu7t5v0_, contact, 0.92, 3.165, 0.22, 0.22, 4, 1, 2.04, 0)
R(gf180mcu_fd_sc_mcu7t5v0_, contact, [(5,0.415,5.22,0.635), (0.68,0.485,0.9,0.705), (11.76,0.485,11.98,0.705), (2.96,0.535,3.18,0.755), (9.08,0.54,9.3,0.76), (14.44,0.54,14.66,0.76), (17.12,0.54,17.34,0.76), (7.04,0.58,7.26,0.8), (19.58,0.78,19.8,1), (3.53,1.29,3.75,1.51), (6.48,1.345,6.7,1.565), (7.58,1.345,7.8,1.565), (10.985,1.51,11.205,1.73), (12.55,1.51,12.77,1.73), (16.35,1.51,16.57,1.73), (17.865,1.51,18.085,1.73), (1.5,1.85,1.72,2.07), (4.49,1.85,4.71,2.07), (5.52,1.85,5.74,2.07), (8.545,1.85,8.765,2.07), (9.8,1.85,10.02,2.07), (19,1.85,19.22,2.07), (13.59,1.97,13.81,2.19), (15.265,1.97,15.485,2.19), (9.13,2.63,9.35,2.85), (19.53,2.63,19.75,2.85), (14.44,2.83,14.66,3.05), (9.13,3.1,9.35,3.32), (19.53,3.1,19.75,3.32), (11.76,3.29,11.98,3.51), (17.035,3.29,17.255,3.51)])
R(gf180mcu_fd_sc_mcu7t5v0_, metal1, [(1.44,1.8,9.035,2.12)])
P(gf180mcu_fd_sc_mcu7t5v0_, metal1, [(1.71,1.21),(1.71,1.57),(7.935,1.57),(7.935,1.34),(3.83,1.34),(3.83,1.21)],
  [(10.84,1.505),(10.84,1.735),(16.08,1.735),(16.08,2.13),(18.25,2.13),(18.25,1.505)],
  [(2.9,0.53),(2.9,0.7),(1.19,0.7),(1.19,0.955),(0.98,0.955),(0.98,2.68),(8.34,2.68),(8.34,2.36),(1.21,2.36),(1.21,1.185),(1.42,1.185),(1.42,0.93),(4.48,0.93),(4.48,1.1),(8.505,1.1),(8.505,1.275),(18.74,1.275),(18.74,0.775),(18.4,0.775),(18.4,1.045),(16.06,1.045),(16.06,0.775),(15.72,0.775),(15.72,1.045),(13.38,1.045),(13.38,0.775),(13.04,0.775),(13.04,1.045),(10.7,1.045),(10.7,0.775),(10.36,0.775),(10.36,1.045),(8.735,1.045),(8.735,0.87),(7.32,0.87),(7.32,0.575),(6.98,0.575),(6.98,0.87),(4.71,0.87),(4.71,0.7),(3.24,0.7),(3.24,0.53)],
  [(9.55,1.8),(9.55,2.12),(10.34,2.12),(10.34,2.595),(18.8,2.595),(18.8,2.12),(19.59,2.12),(19.59,1.8),(18.57,1.8),(18.57,2.36),(15.545,2.36),(15.545,1.965),(15.205,1.965),(15.205,2.36),(13.87,2.36),(13.87,1.965),(13.53,1.965),(13.53,2.36),(10.57,2.36),(10.57,1.8)],
  [(9.07,2.53),(9.07,3.16),(0.86,3.16),(0.86,3.39),(9.41,3.39),(9.41,3.055),(19.525,3.055),(19.525,3.38),(19.755,3.38),(19.755,2.53),(19.525,2.53),(19.525,2.825),(9.41,2.825),(9.41,2.53)],
  [(0,-0.3),(0,0.3),(0.62,0.3),(0.62,0.71),(0.96,0.71),(0.96,0.3),(4.94,0.3),(4.94,0.64),(5.28,0.64),(5.28,0.3),(9.02,0.3),(9.02,0.765),(9.36,0.765),(9.36,0.3),(11.7,0.3),(11.7,0.71),(12.04,0.71),(12.04,0.3),(14.38,0.3),(14.38,0.765),(14.72,0.765),(14.72,0.3),(17.06,0.3),(17.06,0.765),(17.4,0.765),(17.4,0.3),(19.575,0.3),(19.575,1.06),(19.805,1.06),(19.805,0.3),(20.16,0.3),(20.16,-0.3)],
  [(11.7,3.285),(11.7,3.62),(0,3.62),(0,4.22),(20.16,4.22),(20.16,3.62),(17.315,3.62),(17.315,3.285),(16.975,3.285),(16.975,3.62),(12.04,3.62),(12.04,3.285)])
R(gf180mcu_fd_sc_mcu7t5v0_, dualgate, [(-0.28,-0.28,20.44,4.2)])
R(gf180mcu_fd_sc_mcu7t5v0_, v5_xtor, [(0,0,20.16,3.92)])
R(gf180mcu_fd_sc_mcu7t5v0_, lvpwell, [(-0.43,-0.43,20.59,1.76)])
gf180mcu_fd_sc_mcu7t5v0_.add(gdstk.Label('A2', (5.32,1.96), layer=34, texttype=10))
gf180mcu_fd_sc_mcu7t5v0_.add(gdstk.Label('B', (10.36,1.96), layer=34, texttype=10))
gf180mcu_fd_sc_mcu7t5v0_.add(gdstk.Label('C', (16.52,1.96), layer=34, texttype=10))
gf180mcu_fd_sc_mcu7t5v0_.add(gdstk.Label('VDD', (1.4,3.92), layer=34, texttype=10))
gf180mcu_fd_sc_mcu7t5v0_.add(gdstk.Label('VSS', (1.4,0), layer=34, texttype=10))
gf180mcu_fd_sc_mcu7t5v0_.add(gdstk.Label('ZN', (8.12,2.52), layer=34, texttype=10))
gf180mcu_fd_sc_mcu7t5v0_.add(gdstk.Label('A1', (3.64,1.4), layer=34, texttype=10))
gf180mcu_fd_sc_mcu7t5v0_.add(gdstk.Label('& Vendor GLOBALFOUNDRIES', (0,2), layer=63, texttype=63))
gf180mcu_fd_sc_mcu7t5v0_.add(gdstk.Label('& Product GF018hv5v_mcu_sc7', (0,1.5), layer=63, texttype=63))
gf180mcu_fd_sc_mcu7t5v0_.add(gdstk.Label('& Version 2015q2v1', (0,1), layer=63, texttype=63))
gf180mcu_fd_sc_mcu7t5v0_.add(gdstk.Label('& Metric 1.00', (0,0.5), layer=63, texttype=63))
gf180mcu_fd_sc_mcu7t5v0_.add(gdstk.Label('VNW', (0.345,3.92), layer=21, texttype=10))
gf180mcu_fd_sc_mcu7t5v0_.add(gdstk.Label('VPW', (0.34,-0.085), layer=204, texttype=10))

lib.write_gds('gf180mcu_fd_sc_mcu7t5v0__aoi211_4.gds')
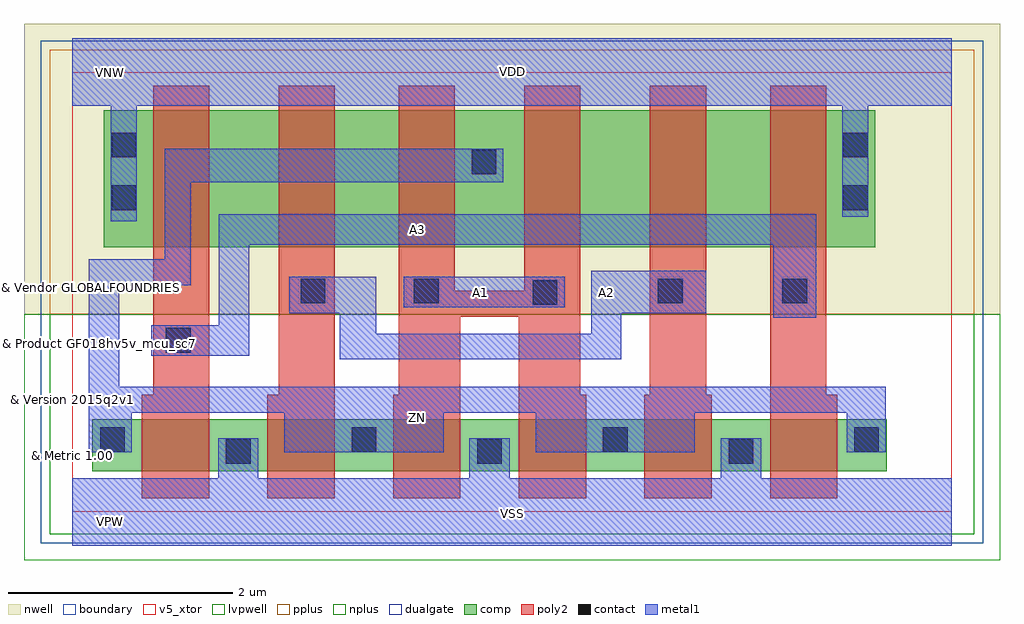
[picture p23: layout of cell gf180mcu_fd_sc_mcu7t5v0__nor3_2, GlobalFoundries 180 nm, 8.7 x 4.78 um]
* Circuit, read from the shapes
.subckt gf180mcu_fd_sc_mcu7t5v0__nor3_2 A1 A2 A3 VDD VNW VSS ZN
XM1 VSS A3 ZN VSUBS nfet_05v0 w=0.465u l=0.6u m=2
XM2 ZN A2 VSS VSUBS nfet_05v0 w=0.465u l=0.6u m=2
XM3 VSS A1 ZN VSUBS nfet_05v0 w=0.465u l=0.6u m=2
XM4 n1 A3 VDD VNW pfet_05v0 w=1.22u l=0.5u
XM5 n2 A2 n1 VNW pfet_05v0 w=1.22u l=0.5u
XM6 ZN A1 n2 VNW pfet_05v0 w=1.22u l=0.5u
XM7 n3 A1 ZN VNW pfet_05v0 w=1.22u l=0.5u
XM8 n4 A2 n3 VNW pfet_05v0 w=1.22u l=0.5u
XM9 VDD A3 n4 VNW pfet_05v0 w=1.22u l=0.5u
.ends

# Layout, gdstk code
import gdstk
lib = gdstk.Library(unit=1e-6, precision=1e-09)
def R(c, l, rs):  # rectangles x0, y0, x1, y1
    for r in rs: c.add(gdstk.rectangle(r[:2], r[2:], *l))
def A(c, l, x, y, w, h, nx, ny, dx, dy):  # array of equal rectangles
    R(c, l, [(x+i*dx, y+j*dy, x+i*dx+w, y+j*dy+h) for i in range(nx) for j in range(ny)])
def P(c, l, *ps):  # polygons
    for p in ps: c.add(gdstk.Polygon(p, *l))
boundary = (0, 0)
nwell = (21, 0)
comp = (22, 0)
poly2 = (30, 0)
pplus = (31, 0)
nplus = (32, 0)
contact = (33, 0)
metal1 = (34, 0)
dualgate = (55, 0)
v5_xtor = (112, 1)
lvpwell = (204, 0)

gf180mcu_fd_sc_mcu7t5v0_ = lib.new_cell('gf180mcu_fd_sc_mcu7t5v0__nor3_2')
R(gf180mcu_fd_sc_mcu7t5v0_, boundary, [(0,0,7.84,3.92)])
R(gf180mcu_fd_sc_mcu7t5v0_, nwell, [(-0.43,1.76,8.27,4.35)])
R(gf180mcu_fd_sc_mcu7t5v0_, comp, [(0.18,0.36,7.26,0.825), (0.28,2.36,7.16,3.58)])
P(gf180mcu_fd_sc_mcu7t5v0_, poly2, [(0.62,0.12),(0.62,1.045),(0.72,1.045),(0.72,3.8),(1.22,3.8),(1.22,0.12)],
  [(1.74,0.12),(1.74,1.045),(1.84,1.045),(1.84,3.8),(2.34,3.8),(2.34,0.12)],
  [(2.86,0.12),(2.86,1.045),(2.91,1.045),(2.91,3.8),(3.41,3.8),(3.41,1.97),(4.03,1.97),(4.03,3.8),(4.53,3.8),(4.53,1.045),(4.58,1.045),(4.58,0.12),(3.98,0.12),(3.98,1.74),(3.46,1.74),(3.46,0.12)],
  [(5.1,0.12),(5.1,1.045),(5.15,1.045),(5.15,3.8),(5.65,3.8),(5.65,1.045),(5.7,1.045),(5.7,0.12)],
  [(6.22,0.12),(6.22,3.8),(6.72,3.8),(6.72,1.045),(6.82,1.045),(6.82,0.12)])
R(gf180mcu_fd_sc_mcu7t5v0_, pplus, [(-0.2,1.76,8.04,4.12)])
R(gf180mcu_fd_sc_mcu7t5v0_, nplus, [(-0.2,-0.2,8.04,1.76)])
A(gf180mcu_fd_sc_mcu7t5v0_, contact, 1.37, 0.43, 0.22, 0.22, 3, 1, 2.24, 0)
A(gf180mcu_fd_sc_mcu7t5v0_, contact, 0.25, 0.535, 0.22, 0.22, 4, 1, 2.24, 0)
R(gf180mcu_fd_sc_mcu7t5v0_, contact, [(0.835,1.42,1.055,1.64), (4.105,1.845,4.325,2.065), (2.035,1.86,2.255,2.08), (3.045,1.86,3.265,2.08), (5.22,1.86,5.44,2.08), (6.33,1.86,6.55,2.08), (0.35,2.69,0.57,2.91), (6.87,2.69,7.09,2.91), (3.56,3.01,3.78,3.23), (0.35,3.16,0.57,3.38), (6.87,3.16,7.09,3.38)])
R(gf180mcu_fd_sc_mcu7t5v0_, metal1, [(2.955,1.825,4.39,2.095)])
P(gf180mcu_fd_sc_mcu7t5v0_, metal1, [(2.385,1.36),(2.385,1.77),(1.935,1.77),(1.935,2.095),(2.71,2.095),(2.71,1.59),(4.625,1.59),(4.625,2.15),(5.65,2.15),(5.65,1.77),(4.895,1.77),(4.895,1.36)],
  [(0.705,1.39),(0.705,1.665),(1.305,1.665),(1.305,2.655),(6.63,2.655),(6.63,1.73),(6.25,1.73),(6.25,2.38),(1.58,2.38),(1.58,1.39)],
  [(0.145,0.53),(0.145,2.25),(0.825,2.25),(0.825,3.235),(3.84,3.235),(3.84,2.94),(1.055,2.94),(1.055,2.02),(0.42,2.02),(0.42,1.115),(7.25,1.115),(7.25,0.53),(6.905,0.53),(6.905,0.885),(5.55,0.885),(5.55,0.53),(4.13,0.53),(4.13,0.885),(3.31,0.885),(3.31,0.53),(1.89,0.53),(1.89,0.885),(0.53,0.885),(0.53,0.53)],
  [(0,-0.3),(0,0.3),(1.3,0.3),(1.3,0.655),(1.66,0.655),(1.66,0.3),(3.54,0.3),(3.54,0.655),(3.9,0.655),(3.9,0.3),(5.78,0.3),(5.78,0.655),(6.14,0.655),(6.14,0.3),(7.84,0.3),(7.84,-0.3)],
  [(0.345,2.59),(0.345,3.62),(0,3.62),(0,4.22),(7.84,4.22),(7.84,3.62),(7.095,3.62),(7.095,2.63),(6.865,2.63),(6.865,3.62),(0.575,3.62),(0.575,2.59)])
R(gf180mcu_fd_sc_mcu7t5v0_, dualgate, [(-0.28,-0.28,8.12,4.2)])
R(gf180mcu_fd_sc_mcu7t5v0_, v5_xtor, [(0,0,7.84,3.92)])
R(gf180mcu_fd_sc_mcu7t5v0_, lvpwell, [(-0.43,-0.43,8.27,1.76)])
gf180mcu_fd_sc_mcu7t5v0_.add(gdstk.Label('A3', (3.08,2.52), layer=34, texttype=10))
gf180mcu_fd_sc_mcu7t5v0_.add(gdstk.Label('VDD', (3.92,3.925), layer=34, texttype=10))
gf180mcu_fd_sc_mcu7t5v0_.add(gdstk.Label('VSS', (3.92,-0.01), layer=34, texttype=10))
gf180mcu_fd_sc_mcu7t5v0_.add(gdstk.Label('ZN', (3.08,0.84), layer=34, texttype=10))
gf180mcu_fd_sc_mcu7t5v0_.add(gdstk.Label('A1', (3.64,1.96), layer=34, texttype=10))
gf180mcu_fd_sc_mcu7t5v0_.add(gdstk.Label('A2', (4.76,1.96), layer=34, texttype=10))
gf180mcu_fd_sc_mcu7t5v0_.add(gdstk.Label('& Vendor GLOBALFOUNDRIES', (0,2), layer=63, texttype=63))
gf180mcu_fd_sc_mcu7t5v0_.add(gdstk.Label('& Product GF018hv5v_mcu_sc7', (0,1.5), layer=63, texttype=63))
gf180mcu_fd_sc_mcu7t5v0_.add(gdstk.Label('& Version 2015q2v1', (0,1), layer=63, texttype=63))
gf180mcu_fd_sc_mcu7t5v0_.add(gdstk.Label('& Metric 1.00', (0,0.5), layer=63, texttype=63))
gf180mcu_fd_sc_mcu7t5v0_.add(gdstk.Label('VNW', (0.345,3.92), layer=21, texttype=10))
gf180mcu_fd_sc_mcu7t5v0_.add(gdstk.Label('VPW', (0.34,-0.085), layer=204, texttype=10))

lib.write_gds('gf180mcu_fd_sc_mcu7t5v0__nor3_2.gds')
